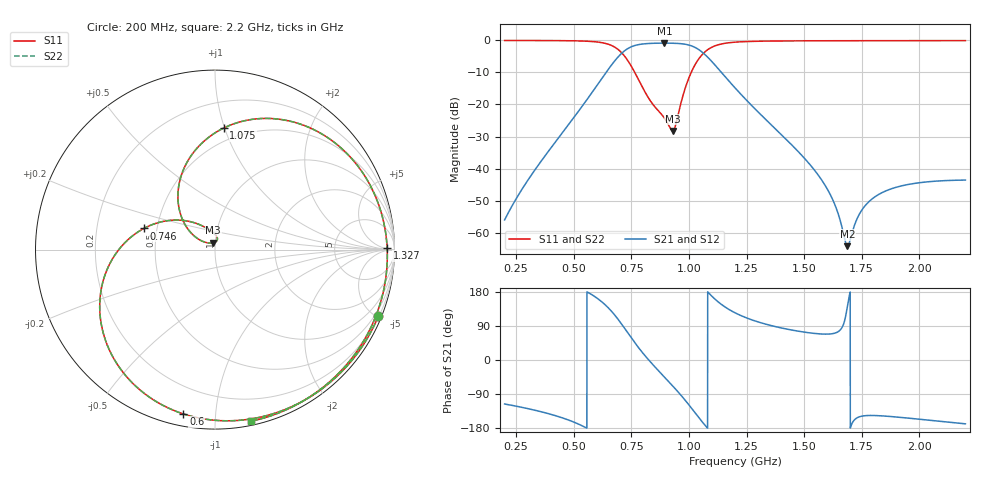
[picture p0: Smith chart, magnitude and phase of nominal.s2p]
! SIMULATED vendor inductor fit + estimated PCB/capacitor parasitics; not measured
# Hz S RI R 50
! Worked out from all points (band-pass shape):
!   4001 points, 200 MHz to 2.2 GHz, reference 50 ohm
!   highest |S21| = -0.98 dB at 893.5 MHz (marker M1); lowest = -63.9 dB at 1.688 GHz (marker M2)
!   |S21| within 3 dB of the highest: 710.3 MHz to 1.061 GHz (350.7 MHz wide, 39.6 % of centre)
!   lowest |S11| = -28.2 dB at 929.5 MHz (marker M3), VSWR 1.08, Z = 48.9 + j3.71 ohm
!   |S11| at or under -10 dB: 764.4 MHz to 1.01 GHz (245.9 MHz wide, 27.7 % of centre)
!   |S22| runs from -28.2 to -0.1 dB; largest |S21 - S12| = 1e-12
!   S11 on the Smith chart (normalised r, x): 200 MHz: 0.23, -5.10; 600 MHz: 0.06, -0.82; 746 MHz: 0.42, +0.12; 1.075 GHz: 0.39, +0.99; 1.327 GHz: 45, +11; 2.2 GHz: 0.03, -1.23
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2e8  0.9105 -0.3704  -0.000713 -0.00146  -0.000713 -0.00146  0.9105 -0.3704
3.92e8  0.6502 -0.7324  -0.0151 -0.0118  -0.0151 -0.0118  0.6502 -0.7324
5.335e8  0.1954 -0.9442  -0.0899 -0.0115  -0.0899 -0.0115  0.1954 -0.9442
6e8  -0.1761 -0.9156  -0.1872 0.0547  -0.1872 0.0547  -0.1761 -0.9156
6.815e8  -0.6324 -0.4227  -0.2151 0.442  -0.2151 0.442  -0.6324 -0.4227
7.46e8  -0.3965 0.1178  0.3669 0.6803  0.3669 0.6803  -0.3965 0.1178
8.05e8  -0.0897 0.1406  0.843 0.2199  0.843 0.2199  -0.0897 0.1406
8.67e8  0.00438 0.0799  0.789 -0.4157  0.789 -0.4157  0.00438 0.0799
8.935e8  0.0137 0.0601  0.6321 -0.6309  0.6321 -0.6309  0.0137 0.0601
9.295e8  -0.00948 0.0378  0.3282 -0.8276  0.3282 -0.8276  -0.00948 0.0378
9.745e8  -0.116 0.0761  -0.1419 -0.8574  -0.1419 -0.8574  -0.116 0.0761
1.0175e9  -0.2067 0.2929  -0.5316 -0.5889  -0.5316 -0.5889  -0.2067 0.2929
1.075e9  0.0485 0.6774  -0.5679 -0.0423  -0.5679 -0.0423  0.0485 0.6774
1.1235e9  0.4388 0.7104  -0.3365 0.1562  -0.3365 0.1562  0.4388 0.7104
1.2e9  0.809 0.448  -0.1028 0.149  -0.1028 0.149  0.809 0.448
1.327e9  0.9591 0.00934  -0.00608 0.0613  -0.00608 0.0613  0.9591 0.00934
1.5335e9  0.8684 -0.4341  0.00353 0.0102  0.00353 0.0102  0.8684 -0.4341
1.6225e9  0.7939 -0.5622  0.00121 0.00322  0.00121 0.00322  0.7939 -0.5622
1.688e9  0.7335 -0.6406  -0.000505 0.000385  -0.000505 0.000385  0.7335 -0.6406
1.7585e9  0.665 -0.7126  -0.00213 -0.00136  -0.00213 -0.00136  0.665 -0.7126
1.867e9  0.555 -0.8024  -0.00407 -0.00247  -0.00407 -0.00247  0.555 -0.8024
2.2e9  0.2032 -0.9559  -0.00659 -0.00135  -0.00659 -0.00135  0.2032 -0.9559
